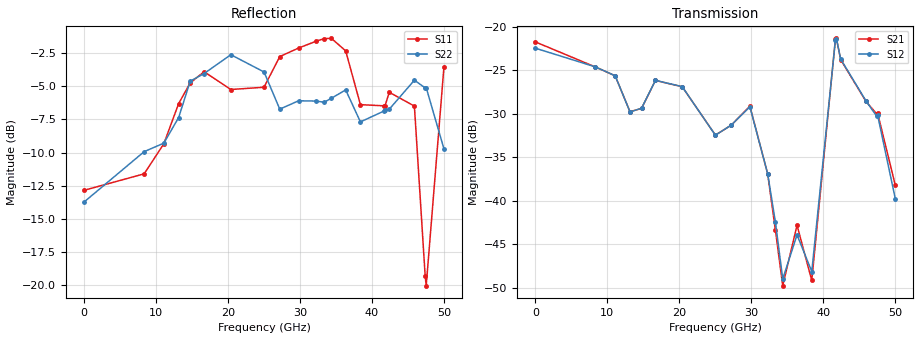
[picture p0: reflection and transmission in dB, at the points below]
!Keysight Technologies,N5245B,MY58422270,A.16.20.02
!Date: Thursday, March 05, 2026 01:26:41
!Correction: S11(C  2-Port  )
!S21(C  2-Port  )
!S12(C  2-Port  )
!S22(C  2-Port  )
!S2P File: Measurements: S11, S21, S12, S22:
# Hz S  dB  R 50
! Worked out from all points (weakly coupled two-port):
!   3201 points, 10 MHz to 50 GHz, reference 50 ohm
!   highest |S21| = -21.35 dB at 41.81 GHz (marker M1); lowest = -49.7 dB at 34.36 GHz (marker M2)
!   lowest |S11| = -20.0 dB at 47.53 GHz (marker M3), VSWR 1.22, Z = 46.1 + j8.79 ohm
!   |S11| at or under -10 dB: start of sweep to 10.13 GHz; 11.35 GHz to 11.93 GHz (572.9 MHz wide, 4.92 % of centre); 46.66 GHz to 48.28 GHz (1.624 GHz wide, 3.42 % of centre)
!   |S22| runs from -18.2 to -2.6 dB; largest |S21 - S12| = 0.0074
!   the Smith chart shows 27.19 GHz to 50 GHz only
!   S11 on the Smith chart (normalised r, x): 27.19 GHz: 0.18, +0.36; 32.27 GHz: 0.42, +1.83; 36.35 GHz: 2.44, -3.41; 42.41 GHz: 1.02, -1.27; 47.39 GHz: 0.84, +0.11; 50 GHz: 0.62, -1.35
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1e7  -12.84 -4.4  -21.76 6.7  -22.48 5.6  -13.72 35.8
8.352081e9  -11.60 174.8  -24.64 28.8  -24.63 28.6  -9.93 -169.9
1.108591e10  -9.34 109.3  -25.65 -73.9  -25.64 -73.9  -9.29 86.6
1.3148e10  -6.31 64.8  -29.77 -131.8  -29.80 -132.0  -7.36 -22.0
1.475705e10  -4.75 13.3  -29.39 -153.0  -29.37 -152.9  -4.62 -90.3
1.667854e10  -3.91 -43.8  -26.18 157.8  -26.17 157.7  -4.05 -141.0
2.039655e10  -5.25 -121.3  -26.91 40.0  -26.89 39.8  -2.63 155.3
2.5005e10  -5.08 179.8  -32.45 -66.1  -32.47 -66.4  -3.93 71.7
2.719206e10  -2.77 139.5  -31.33 -113.7  -31.32 -114.5  -6.73 32.5
2.980092e10  -2.13 94.3  -29.14 161.1  -29.21 160.7  -6.10 -27.7
3.226917e10  -1.61 55.3  -36.91 50.1  -36.90 50.2  -6.12 -102.7
3.334708e10  -1.42 36.1  -43.40 4.7  -42.47 4.6  -6.21 -126.5
3.43625e10  -1.40 18.0  -49.75 -89.2  -48.98 -92.2  -5.91 -148.0
3.634648e10  -2.34 -22.4  -42.81 112.3  -43.91 113.2  -5.28 174.2
3.839295e10  -6.39 -22.4  -49.15 -119.5  -48.13 106.4  -7.69 141.5
4.167354e10  -6.48 -52.5  -21.46 -55.3  -21.58 -55.9  -6.87 115.3
4.181414e10  -6.46 -52.5  -21.35 -68.7  -21.37 -68.6  -6.76 114.1
4.240777e10  -5.46 -56.9  -23.79 -114.0  -23.73 -114.0  -6.73 109.9
4.589145e10  -6.50 -117.2  -28.55 49.8  -28.49 50.3  -4.55 62.6
4.739115e10  -19.32 141.2  -30.01 2.2  -30.27 2.0  -5.13 43.2
4.753174e10  -20.02 108.8  -29.92 -0.4  -30.14 -0.0  -5.11 41.7
5e10  -3.52 -65.8  -38.23 -133.8  -39.78 -133.5  -9.73 4.7
